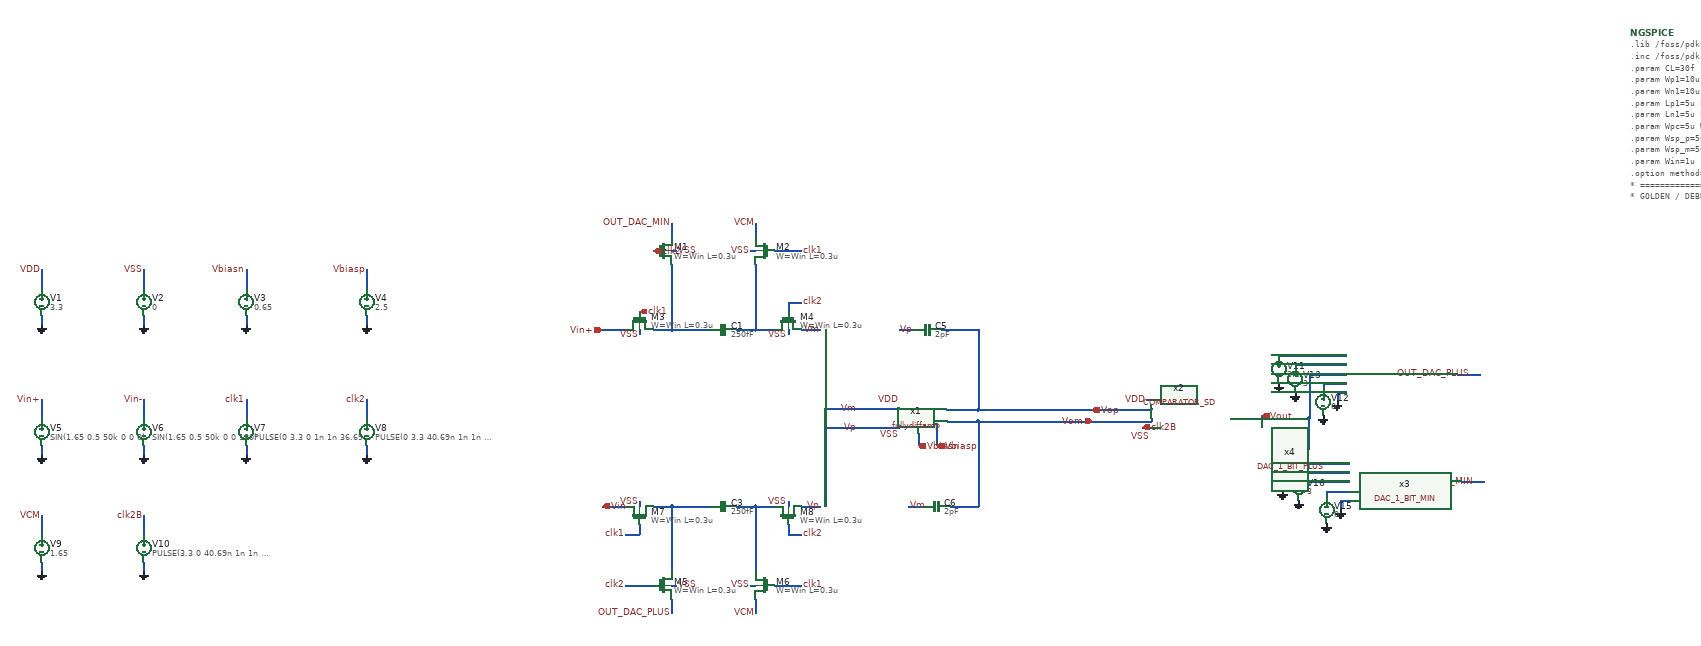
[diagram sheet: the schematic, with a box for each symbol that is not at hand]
v {xschem version=3.4.8RC file_version=1.3}
G {}
K {}
V {}
S {}
F {}
E {}
N -406.25 -788.75 -406.25 -648.75 {lab=#net1}
N -446.25 -648.75 -406.25 -648.75 {lab=#net1}
N -406.25 -648.75 -326.25 -648.75 {lab=#net1}
N -266.25 -648.75 -226.25 -648.75 {lab=#net2}
N -226.25 -788.75 -226.25 -648.75 {lab=#net2}
N -226.25 -648.75 -186.25 -648.75 {lab=#net2}
N -126.25 -648.75 -86.25 -648.75 {lab=Vm}
N -526.25 -648.75 -506.25 -648.75 {lab=Vin+}
N -556.25 -648.75 -526.25 -648.75 {lab=Vin+}
N -156.25 -708.75 -156.25 -688.75 {lab=clk2}
N -156.25 -708.75 -126.25 -708.75 {lab=clk2}
N -186.25 -818.75 -126.25 -818.75 {lab=clk1}
N -226.25 -878.75 -226.25 -848.75 {lab=VCM}
N -406.25 -878.75 -406.25 -848.75 {lab=OUT_DAC_MIN}
N -406.25 -268.75 -406.25 -128.75 {lab=#net3}
N -446.25 -268.75 -406.25 -268.75 {lab=#net3}
N -406.25 -268.75 -326.25 -268.75 {lab=#net3}
N -266.25 -268.75 -226.25 -268.75 {lab=#net4}
N -226.25 -268.75 -226.25 -128.75 {lab=#net4}
N -226.25 -268.75 -186.25 -268.75 {lab=#net4}
N -126.25 -268.75 -86.25 -268.75 {lab=Vp}
N -526.25 -268.75 -506.25 -268.75 {lab=Vin-}
N -556.25 -268.75 -526.25 -268.75 {lab=Vin-}
N -476.25 -228.75 -476.25 -208.75 {lab=clk1}
N -506.25 -208.75 -476.25 -208.75 {lab=clk1}
N -506.25 -98.75 -446.25 -98.75 {lab=clk2}
N -156.25 -228.75 -156.25 -208.75 {lab=clk2}
N -156.25 -208.75 -126.25 -208.75 {lab=clk2}
N -186.25 -98.75 -126.25 -98.75 {lab=clk1}
N -226.25 -68.75 -226.25 -38.75 {lab=VCM}
N -406.25 -68.75 -406.25 -38.75 {lab=OUT_DAC_PLUS}
N -406.25 -818.75 -396.25 -818.75 {lab=VSS}
N -236.25 -818.75 -226.25 -818.75 {lab=VSS}
N -476.25 -648.75 -476.25 -638.75 {lab=VSS}
N -156.25 -648.75 -156.25 -638.75 {lab=VSS}
N -476.25 -278.75 -476.25 -268.75 {lab=VSS}
N -156.25 -278.75 -156.25 -268.75 {lab=VSS}
N -406.25 -98.75 -396.25 -98.75 {lab=VSS}
N -236.25 -98.75 -226.25 -98.75 {lab=VSS}
N 83.75 -648.75 113.75 -648.75 {lab=Vp}
N 103.75 -268.75 133.75 -268.75 {lab=Vm}
N -76.25 -648.75 -76.25 -478.75 {lab=Vm}
N -76.25 -478.75 83.75 -478.75 {lab=Vm}
N -76.25 -438.75 -76.25 -268.75 {lab=Vp}
N -76.25 -438.75 83.75 -438.75 {lab=Vp}
N 83.75 -443.75 83.75 -438.75 {lab=Vp}
N 173.75 -648.75 243.75 -648.75 {lab=Vop}
N 193.75 -268.75 253.75 -268.75 {lab=Vom}
N 186.25 -452.5 253.75 -452.5 {lab=Vom}
N 185 -476.25 252.5 -476.25 {lab=Vop}
N 243.75 -648.75 253.75 -648.75 {lab=Vop}
N 252.5 -476.25 253.75 -476.25 {lab=Vop}
N 253.75 -648.75 253.75 -476.25 {lab=Vop}
N 253.75 -452.5 253.75 -268.75 {lab=Vom}
N 156.25 -446.25 163.75 -446.25 {lab=Vbiasp}
N 163.75 -446.25 163.75 -398.75 {lab=Vbiasp}
N 123.75 -426.25 123.75 -398.75 {lab=Vbiasn}
N 253.75 -476.25 296.25 -476.25 {lab=Vop}
N 253.75 -452.5 296.25 -452.5 {lab=Vom}
N 476.25 -476.25 626.25 -476.25 {lab=Vop}
N 626.25 -478.75 626.25 -476.25 {lab=Vop}
N 476.25 -452.5 626.25 -452.5 {lab=Vom}
N 626.25 -458.75 626.25 -452.5 {lab=Vom}
N 796.25 -458.75 966.25 -458.75 {lab=Vout}
N 298.75 -476.25 346.25 -476.25 {lab=Vop}
N 298.75 -452.5 346.25 -452.5 {lab=Vom}
N 296.25 -476.25 298.75 -476.25 {lab=Vop}
N 296.25 -452.5 298.75 -452.5 {lab=Vom}
N -1763.75 -778.75 -1763.75 -738.75 {lab=VDD}
N -1763.75 -678.75 -1763.75 -658.75 {lab=0}
N -1543.75 -778.75 -1543.75 -738.75 {lab=VSS}
N -1543.75 -678.75 -1543.75 -658.75 {lab=0}
N -1323.75 -778.75 -1323.75 -738.75 {lab=Vbiasn}
N -1323.75 -678.75 -1323.75 -658.75 {lab=0}
N -1063.75 -778.75 -1063.75 -738.75 {lab=Vbiasp}
N -1063.75 -678.75 -1063.75 -658.75 {lab=0}
N -1763.75 -498.75 -1763.75 -458.75 {lab=Vin+}
N -1763.75 -398.75 -1763.75 -378.75 {lab=0}
N -1543.75 -498.75 -1543.75 -458.75 {lab=Vin-}
N -1543.75 -398.75 -1543.75 -378.75 {lab=0}
N -1323.75 -498.75 -1323.75 -458.75 {lab=clk1}
N -1323.75 -398.75 -1323.75 -378.75 {lab=0}
N -1063.75 -498.75 -1063.75 -458.75 {lab=clk2}
N -1063.75 -398.75 -1063.75 -378.75 {lab=0}
N -1763.75 -248.75 -1763.75 -208.75 {lab=VCM}
N -1763.75 -148.75 -1763.75 -128.75 {lab=0}
N -1543.75 -248.75 -1543.75 -208.75 {lab=clk2B}
N -1543.75 -148.75 -1543.75 -128.75 {lab=0}
N 346.25 -476.25 476.25 -476.25 {lab=Vop}
N 346.25 -452.5 476.25 -452.5 {lab=Vom}
N 607.1875 -439.0625 626.25 -438.75 {lab=clk2B}
N 615.9375 -498.75 626.25 -498.75 {lab=VDD}
N 863.75 -463.75 863.75 -458.75 {lab=Vout}
N 996.25 -533.75 1046.25 -533.75 {lab=#net5}
N 996.25 -533.75 996.25 -523.75 {lab=#net5}
N 966.25 -553.75 1046.25 -553.75 {lab=Vout}
N 901.25 -593.75 1046.25 -593.75 {lab=#net6}
N 966.25 -553.75 966.25 -458.75 {lab=Vout}
N 1026.25 -513.75 1046.25 -513.75 {lab=0}
N 1026.25 -513.75 1026.25 -493.75 {lab=0}
N 936.25 -573.75 1046.25 -573.75 {lab=#net7}
N 1003.75 -301.25 1053.75 -301.25 {lab=#net8}
N 1003.75 -301.25 1003.75 -291.25 {lab=#net8}
N 973.75 -321.25 1053.75 -321.25 {lab=Vout}
N 908.75 -361.25 1053.75 -361.25 {lab=#net9}
N 1033.75 -281.25 1053.75 -281.25 {lab=0}
N 1033.75 -281.25 1033.75 -261.25 {lab=0}
N 943.75 -341.25 1053.75 -341.25 {lab=#net10}
N 1293.75 -321.25 1343.75 -321.25 {lab=OUT_DAC_MIN}
N 972.5 -321.25 973.75 -321.25 {lab=Vout}
N 963.75 -321.25 972.5 -321.25 {lab=Vout}
N 963.75 -321.25 966.25 -458.75 {lab=Vout}
N 1285 -553.75 1336.25 -553.75 {lab=OUT_DAC_PLUS}
C {symbols/nfet_03v3.sym} -426.25 -818.75 2 1 {name=M1
L=0.3u
W=Win
nf=1
m=1
ad="'int((nf+1)/2) * W/nf * 0.18u'"
pd="'2*int((nf+1)/2) * (W/nf + 0.18u)'"
as="'int((nf+2)/2) * W/nf * 0.18u'"
ps="'2*int((nf+2)/2) * (W/nf + 0.18u)'"
nrd="'0.18u / W'" nrs="'0.18u / W'"
sa=0 sb=0 sd=0
model=nfet_03v3
spiceprefix=X
}
C {symbols/nfet_03v3.sym} -206.25 -818.75 2 0 {name=M2
L=0.3u
W=Win
nf=1
m=1
ad="'int((nf+1)/2) * W/nf * 0.18u'"
pd="'2*int((nf+1)/2) * (W/nf + 0.18u)'"
as="'int((nf+2)/2) * W/nf * 0.18u'"
ps="'2*int((nf+2)/2) * (W/nf + 0.18u)'"
nrd="'0.18u / W'" nrs="'0.18u / W'"
sa=0 sb=0 sd=0
model=nfet_03v3
spiceprefix=X
}
C {symbols/nfet_03v3.sym} -476.25 -668.75 3 1 {name=M3
L=0.3u
W=Win
nf=1
m=1
ad="'int((nf+1)/2) * W/nf * 0.18u'"
pd="'2*int((nf+1)/2) * (W/nf + 0.18u)'"
as="'int((nf+2)/2) * W/nf * 0.18u'"
ps="'2*int((nf+2)/2) * (W/nf + 0.18u)'"
nrd="'0.18u / W'" nrs="'0.18u / W'"
sa=0 sb=0 sd=0
model=nfet_03v3
spiceprefix=X
}
C {symbols/nfet_03v3.sym} -156.25 -668.75 3 1 {name=M4
L=0.3u
W=Win
nf=1
m=1
ad="'int((nf+1)/2) * W/nf * 0.18u'"
pd="'2*int((nf+1)/2) * (W/nf + 0.18u)'"
as="'int((nf+2)/2) * W/nf * 0.18u'"
ps="'2*int((nf+2)/2) * (W/nf + 0.18u)'"
nrd="'0.18u / W'" nrs="'0.18u / W'"
sa=0 sb=0 sd=0
model=nfet_03v3
spiceprefix=X
}
C {capa.sym} -296.25 -648.75 1 1 {name=C1
m=1
value=250fF
footprint=1206
device="ceramic capacitor"}
C {ipin.sym} -556.25 -648.75 0 0 {name=p3 lab=Vin+}
C {lab_pin.sym} -126.25 -818.75 2 0 {name=p1 sig_type=std_logic lab=clk1}
C {lab_pin.sym} -126.25 -708.75 2 0 {name=p5 sig_type=std_logic lab=clk2}
C {symbols/nfet_03v3.sym} -426.25 -98.75 0 0 {name=M5
L=0.3u
W=Win
nf=1
m=1
ad="'int((nf+1)/2) * W/nf * 0.18u'"
pd="'2*int((nf+1)/2) * (W/nf + 0.18u)'"
as="'int((nf+2)/2) * W/nf * 0.18u'"
ps="'2*int((nf+2)/2) * (W/nf + 0.18u)'"
nrd="'0.18u / W'" nrs="'0.18u / W'"
sa=0 sb=0 sd=0
model=nfet_03v3
spiceprefix=X
}
C {symbols/nfet_03v3.sym} -206.25 -98.75 0 1 {name=M6
L=0.3u
W=Win
nf=1
m=1
ad="'int((nf+1)/2) * W/nf * 0.18u'"
pd="'2*int((nf+1)/2) * (W/nf + 0.18u)'"
as="'int((nf+2)/2) * W/nf * 0.18u'"
ps="'2*int((nf+2)/2) * (W/nf + 0.18u)'"
nrd="'0.18u / W'" nrs="'0.18u / W'"
sa=0 sb=0 sd=0
model=nfet_03v3
spiceprefix=X
}
C {symbols/nfet_03v3.sym} -476.25 -248.75 3 0 {name=M7
L=0.3u
W=Win
nf=1
m=1
ad="'int((nf+1)/2) * W/nf * 0.18u'"
pd="'2*int((nf+1)/2) * (W/nf + 0.18u)'"
as="'int((nf+2)/2) * W/nf * 0.18u'"
ps="'2*int((nf+2)/2) * (W/nf + 0.18u)'"
nrd="'0.18u / W'" nrs="'0.18u / W'"
sa=0 sb=0 sd=0
model=nfet_03v3
spiceprefix=X
}
C {symbols/nfet_03v3.sym} -156.25 -248.75 3 0 {name=M8
L=0.3u
W=Win
nf=1
m=1
ad="'int((nf+1)/2) * W/nf * 0.18u'"
pd="'2*int((nf+1)/2) * (W/nf + 0.18u)'"
as="'int((nf+2)/2) * W/nf * 0.18u'"
ps="'2*int((nf+2)/2) * (W/nf + 0.18u)'"
nrd="'0.18u / W'" nrs="'0.18u / W'"
sa=0 sb=0 sd=0
model=nfet_03v3
spiceprefix=X
}
C {capa.sym} -296.25 -268.75 1 0 {name=C3
m=1
value=250fF
footprint=1206
device="ceramic capacitor"}
C {ipin.sym} -556.25 -268.75 2 1 {name=p6 lab=Vin-}
C {lab_pin.sym} -126.25 -98.75 0 1 {name=p7 sig_type=std_logic lab=clk1}
C {lab_pin.sym} -506.25 -208.75 2 1 {name=p8 sig_type=std_logic lab=clk1}
C {lab_pin.sym} -506.25 -98.75 2 1 {name=p9 sig_type=std_logic lab=clk2}
C {lab_pin.sym} -126.25 -208.75 0 1 {name=p10 sig_type=std_logic lab=clk2}
C {lab_pin.sym} -396.25 -818.75 2 0 {name=p13 sig_type=std_logic lab=VSS}
C {lab_pin.sym} -236.25 -818.75 0 0 {name=p14 sig_type=std_logic lab=VSS}
C {lab_pin.sym} -476.25 -638.75 3 0 {name=p15 sig_type=std_logic lab=VSS}
C {lab_pin.sym} -156.25 -638.75 3 0 {name=p16 sig_type=std_logic lab=VSS}
C {lab_pin.sym} -476.25 -278.75 1 0 {name=p17 sig_type=std_logic lab=VSS}
C {lab_pin.sym} -156.25 -278.75 1 0 {name=p18 sig_type=std_logic lab=VSS}
C {lab_pin.sym} -396.25 -98.75 2 0 {name=p19 sig_type=std_logic lab=VSS}
C {lab_pin.sym} -236.25 -98.75 0 0 {name=p20 sig_type=std_logic lab=VSS}
C {capa.sym} 143.75 -648.75 3 0 {name=C5
m=1
value=2pF
footprint=1206
device="ceramic capacitor"}
C {capa.sym} 163.75 -268.75 3 0 {name=C6
m=1
value=2pF
footprint=1206
device="ceramic capacitor"}
C {opin.sym} 498.75 -476.25 3 0 {name=p11 lab=Vop}
C {opin.sym} 500 -452.5 3 1 {name=p12 lab=Vom}
C {lab_pin.sym} 83.75 -423.75 0 0 {name=p23 sig_type=std_logic lab=VSS}
C {lab_pin.sym} 83.75 -498.75 0 0 {name=p24 sig_type=std_logic lab=VDD}
C {lab_pin.sym} -226.25 -38.75 3 0 {name=p38 sig_type=std_logic lab=VCM}
C {lab_pin.sym} -226.25 -878.75 1 0 {name=p39 sig_type=std_logic lab=VCM}
C {ipin.sym} -476.25 -688.75 3 1 {name=p41 lab=clk1}
C {ipin.sym} -446.25 -818.75 2 1 {name=p2 lab=clk2}
C {ipin.sym} 123.75 -398.75 1 1 {name=p4 lab=Vbiasn}
C {ipin.sym} 163.75 -398.75 1 1 {name=p42 lab=Vbiasp}
C {lab_pin.sym} -6.25 -478.75 1 0 {name=p33 sig_type=std_logic lab=Vm}
C {lab_pin.sym} -6.25 -438.75 3 0 {name=p34 sig_type=std_logic lab=Vp}
C {lab_pin.sym} 615.9375 -498.75 0 0 {name=p46 sig_type=std_logic lab=VDD}
C {lab_pin.sym} 626.25 -418.75 0 0 {name=p47 sig_type=std_logic lab=VSS}
C {ipin.sym} 607.1875 -439.0625 2 1 {name=p57 lab=clk2B}
C {vsource.sym} -1763.75 -708.75 0 0 {name=V1 value=3.3 savecurrent=false}
C {gnd.sym} -1763.75 -658.75 0 0 {name=l5 lab=0}
C {vsource.sym} -1543.75 -708.75 0 0 {name=V2 value=0 savecurrent=false}
C {gnd.sym} -1543.75 -658.75 0 0 {name=l6 lab=0}
C {vsource.sym} -1323.75 -708.75 0 0 {name=V3 value=0.65 savecurrent=false}
C {gnd.sym} -1323.75 -658.75 0 0 {name=l7 lab=0}
C {vsource.sym} -1063.75 -708.75 0 0 {name=V4 value=2.5 savecurrent=false}
C {gnd.sym} -1063.75 -658.75 0 0 {name=l8 lab=0}
C {vsource.sym} -1763.75 -428.75 0 0 {name=V5 value="SIN(1.65 0.5 50k 0 0 0)" savecurrent=false}
C {gnd.sym} -1763.75 -378.75 0 0 {name=l9 lab=0}
C {vsource.sym} -1543.75 -428.75 0 0 {name=V6 value="SIN(1.65 0.5 50k 0 0 180)" savecurrent=false}
C {gnd.sym} -1543.75 -378.75 0 0 {name=l10 lab=0}
C {vsource.sym} -1323.75 -428.75 0 0 {name=V7 value="PULSE(0 3.3 0 1n 1n 36.69n 81.38n)" savecurrent=false}
C {gnd.sym} -1323.75 -378.75 0 0 {name=l11 lab=0}
C {vsource.sym} -1063.75 -428.75 0 0 {name=V8 value="PULSE(0 3.3 40.69n 1n 1n 36.69n 81.38n)" savecurrent=false}
C {gnd.sym} -1063.75 -378.75 0 0 {name=l12 lab=0}
C {lab_pin.sym} -1763.75 -778.75 1 0 {name=p25 sig_type=std_logic lab=VDD}
C {lab_pin.sym} -1543.75 -778.75 1 0 {name=p26 sig_type=std_logic lab=VSS
}
C {lab_pin.sym} -1323.75 -778.75 1 0 {name=p27 sig_type=std_logic lab=Vbiasn
}
C {lab_pin.sym} -1063.75 -778.75 1 0 {name=p28 sig_type=std_logic lab=Vbiasp
}
C {lab_pin.sym} -1763.75 -498.75 1 0 {name=p29 sig_type=std_logic lab=Vin+}
C {lab_pin.sym} -1543.75 -498.75 1 0 {name=p30 sig_type=std_logic lab=Vin-}
C {lab_pin.sym} -1323.75 -498.75 1 0 {name=p31 sig_type=std_logic lab=clk1}
C {lab_pin.sym} -1063.75 -498.75 1 0 {name=p32 sig_type=std_logic lab=clk2}
C {vsource.sym} -1763.75 -178.75 0 0 {name=V9 value=1.65 savecurrent=false}
C {gnd.sym} -1763.75 -128.75 0 0 {name=l1 lab=0}
C {lab_pin.sym} -1763.75 -248.75 1 0 {name=p35 sig_type=std_logic lab=VCM}
C {devices/code_shown.sym} 1658.125 -1289.375 0 0 {name=NGSPICE only_toplevel=true
value="
.lib /foss/pdks/gf180mcuD/libs.tech/ngspice/sm141064.ngspice typical
.inc /foss/pdks/gf180mcuD/libs.tech/ngspice/design.ngspice

.param CL=30f
.param Wp1=10u Wp2=1u Wp3=0.5u
.param Wn1=10u Wn2=10u Wn3=5u Wn4=0.5u
.param Lp1=5u Lp2=2u Lp3=5u
.param Ln1=5u Ln2=2u Ln3=0.35u Ln4=15u
.param Wpc=5u Wnc=2.5u Wsc=2*Wpc Lc=0.3u
.param Wsp_p=5u Wsn_p=0.3u Ld=0.3u Wdp_p=40u Wdn_p=0.6u Wsp2_p=5u Wsn2_p=0.3u
.param Wsp_m=5u Wsn_m=0.5u Wdp_m=10u Wdn_m=1u
.param Win=1u
.option method=gear maxord=2 reltol=1e-4

* ================================================================
* GOLDEN / DEBUG-ONLY HELPERS
* x1 (OTA), x2 (comparator), x3/x4 (DAC) are grey and spice_ignore.
* These behavioral blocks verify loop polarity and switched-cap wiring.
* They are NOT layout-ready replacements for the transistor blocks.
* ================================================================
* Behavioral OTA disabled: x1 transistor OTA is active.
* BOP OPA_DRV 0 V=V(VCM)+1.5*tanh(300*(V(Vm)-V(Vp)))
* BOM OMA_DRV 0 V=V(VCM)-1.5*tanh(300*(V(Vm)-V(Vp)))
* ROP OPA_DRV Vop 50
* ROM OMA_DRV Vom 50
RIP Vp VCM 1G
RIM Vm VCM 1G

* Behavioral quantizer disabled: x2 transistor comparator is active.
* BDEC VDEC 0 V=1.65*(1+tanh(50*(V(Vop)-V(Vom))))
* SDEC VDEC Vout clk1 0 SWQ
* CHOLD Vout 0 100f IC=0
* RHOLD Vout 0 1T
* .model SWQ SW(Ron=1 Roff=1e15 Vt=1.65 Vh=0.1)

* Behavioral DAC disabled: x3/x4 transistor DACs are active.
* BDACP DACP_DRV 0 V=1.65*(1-tanh(50*(V(Vout)-1.65)))
* BDACM DACM_DRV 0 V=1.65*(1+tanh(50*(V(Vout)-1.65)))
* RDACP DACP_DRV OUT_DAC_PLUS 10
* RDACM DACM_DRV OUT_DAC_MIN 10

CLP Vop 0 \{CL\}
CLM Vom 0 \{CL\}
RLEAKP Vop 0 1T
RLEAKM Vom 0 1T

* Dummy loads so clock nets always have a DC path.
Rd1 clk1  0 1meg
Rd2 clk2  0 1meg

.control
save all
set color0=white
set color1=black
tran 10n 120u 0 2n
let vicm_ota = (v(Vp)+v(Vm))/2
let vid_ota  = v(Vp)-v(Vm)
let vocm=(v(Vop)+v(Vom))/2
let vod=v(Vop)-v(Vom)
let bit_norm=v(Vout)/3.3

meas tran vocm_first_avg AVG vocm from=10u to=50u
meas tran vocm_second_avg AVG vocm from=60u to=100u
meas tran duty_first AVG bit_norm from=10u to=50u
meas tran duty_second AVG bit_norm from=60u to=100u
meas tran vod_first_avg AVG vod from=10u to=50u
meas tran vod_second_avg AVG vod from=60u to=100u
meas tran vod_min MIN vod from=10u to=100u
meas tran vod_max MAX vod from=10u to=100u

plot v(clk1) v(clk2) v(clk2B)
plot v(Vin+) v(Vin-)
plot v(Vop) v(Vom)
plot vod
plot v(Vout)
plot v(OUT_DAC_PLUS) v(OUT_DAC_MIN)
.endc
.end
"}
C {vsource.sym} -1543.75 -178.75 0 0 {name=V10 value="PULSE(3.3 0 40.69n 1n 1n 36.69n 81.38n)" savecurrent=false}
C {gnd.sym} -1543.75 -128.75 0 0 {name=l2 lab=0}
C {lab_pin.sym} -1543.75 -248.75 1 0 {name=p22 sig_type=std_logic lab=clk2B}
C {opin.sym} 863.75 -463.75 3 0 {name=p52 lab=Vout}
C {vsource.sym} 901.25 -563.75 0 0 {name=V11 value=3.3 savecurrent=false}
C {gnd.sym} 901.25 -533.75 0 0 {name=l3 lab=0}
C {gnd.sym} 1026.25 -493.75 0 0 {name=l4 lab=0}
C {vsource.sym} 996.25 -493.75 0 0 {name=V12 value=0 savecurrent=false}
C {gnd.sym} 936.25 -513.75 0 0 {name=l13 lab=0}
C {noconn.sym} 1336.25 -553.75 1 0 {name=l15}
C {vsource.sym} 936.25 -543.75 0 0 {name=V13 value=3 savecurrent=false}
C {gnd.sym} 996.25 -463.75 0 0 {name=l16 lab=0}
C {vsource.sym} 908.75 -331.25 0 0 {name=V14 value=3.3 savecurrent=false}
C {gnd.sym} 908.75 -301.25 0 0 {name=l14 lab=0}
C {gnd.sym} 1033.75 -261.25 0 0 {name=l17 lab=0}
C {vsource.sym} 1003.75 -261.25 0 0 {name=V15 value=0 savecurrent=false}
C {gnd.sym} 943.75 -281.25 0 0 {name=l18 lab=0}
C {lab_pin.sym} 1323.75 -321.25 1 0 {name=p37 sig_type=std_logic lab=OUT_DAC_MIN}
C {noconn.sym} 1343.75 -321.25 1 0 {name=l19}
C {vsource.sym} 943.75 -311.25 0 0 {name=V16 value=3 savecurrent=false}
C {gnd.sym} 1003.75 -231.25 0 0 {name=l20 lab=0}
C {lab_pin.sym} 1314.375 -553.75 1 0 {name=p40 sig_type=std_logic lab=OUT_DAC_PLUS}
C {lab_pin.sym} -406.25 -38.75 3 0 {name=p43 sig_type=std_logic lab=OUT_DAC_PLUS}
C {lab_pin.sym} -406.25 -878.75 1 0 {name=p36 sig_type=std_logic lab=OUT_DAC_MIN}
C {lab_pin.sym} -86.25 -648.75 0 0 {name=p58 sig_type=std_logic lab=Vm}
C {lab_pin.sym} -86.25 -268.75 0 0 {name=p59 sig_type=std_logic lab=Vp}
C {lab_pin.sym} 83.75 -648.75 2 0 {name=p60 sig_type=std_logic lab=Vp}
C {lab_pin.sym} 103.75 -268.75 2 0 {name=p61 sig_type=std_logic lab=Vm}
C {fully_differential_amplifier/fullydiffamp.sym} 143.75 -373.75 0 0 {name=x1}
C {latched_comparator/COMPARATOR_SD.sym} 606.25 -298.75 0 0 {name=x2}
C {dac_1bit/DAC_1_BIT_PLUS.sym} 1016.25 -463.75 0 0 {name=x4}
C {dac_1bit/DAC_1_BIT_MIN.sym} 1143.75 -191.25 0 0 {name=x3}
